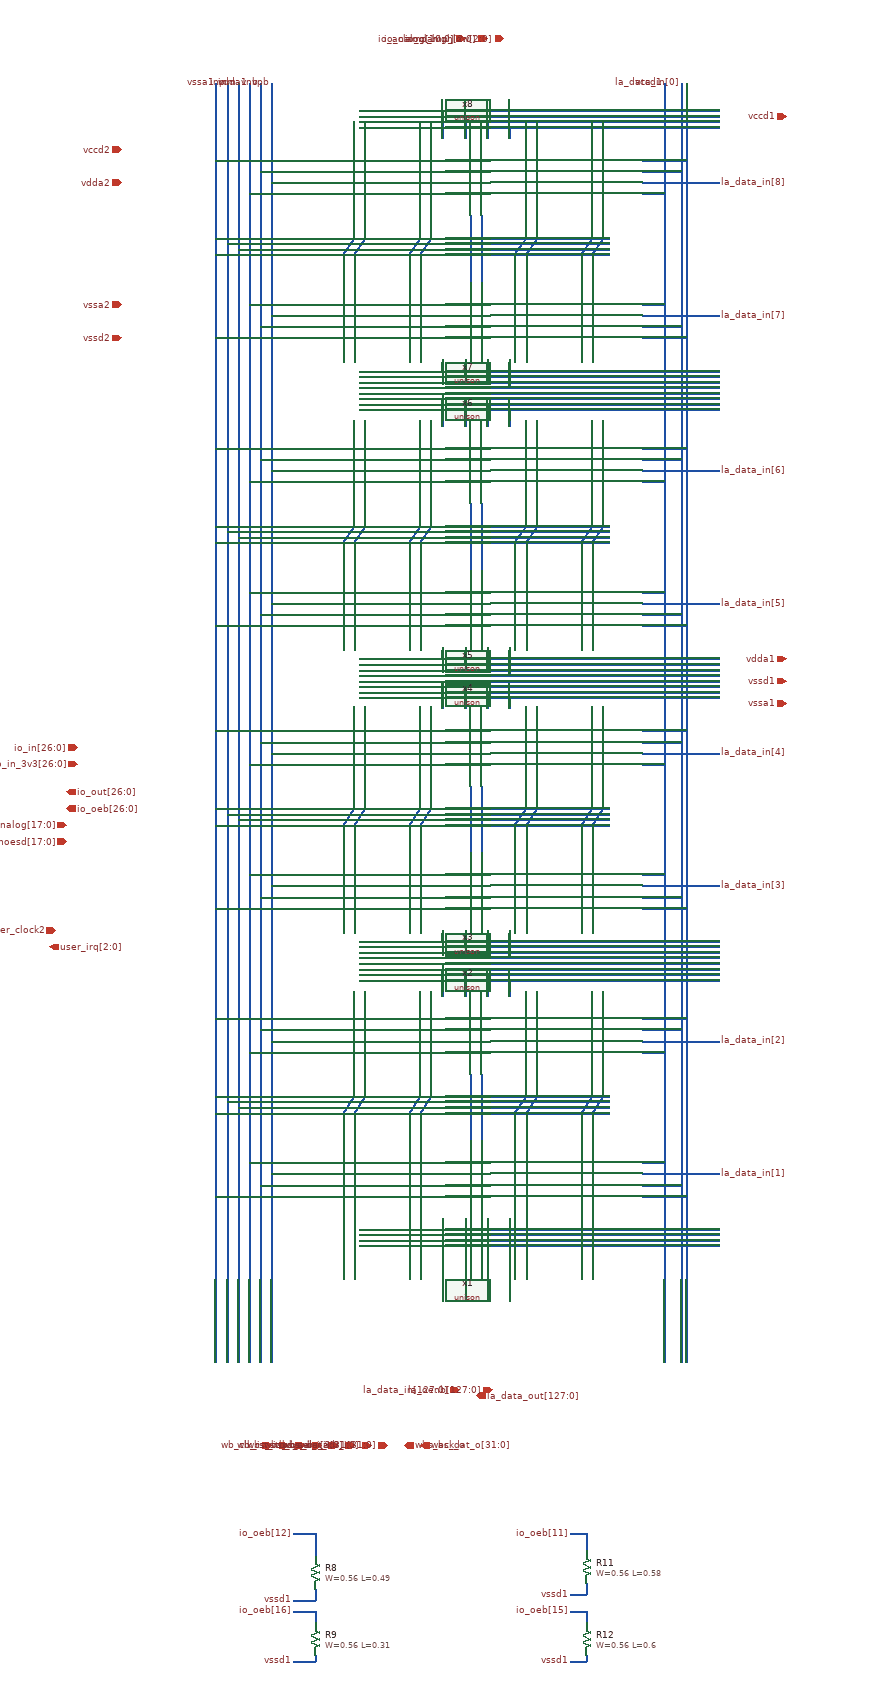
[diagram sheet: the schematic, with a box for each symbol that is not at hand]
v {xschem version=3.0.0 file_version=1.2 }
G {}
K {}
V {}
S {}
E {}
N -290 1540 -290 1580 { lab=io_oeb[12]}
N -290 1640 -290 1660 { lab=vssd1}
N -290 1680 -290 1700 { lab=io_oeb[16]}
N -290 1760 -290 1770 { lab=vssd1}
N 200 1540 200 1570 { lab=io_oeb[11]}
N 200 1630 200 1650 { lab=vssd1}
N 200 1680 200 1700 { lab=io_oeb[15]}
N 200 1760 200 1770 { lab=vssd1}
N -330 1540 -290 1540 { lab=io_oeb[12]}
N -330 1660 -290 1660 { lab=vssd1}
N -330 1680 -290 1680 { lab=io_oeb[16]}
N -330 1770 -290 1770 { lab=vssd1}
N 170 1540 200 1540 { lab=io_oeb[11]}
N 170 1650 200 1650 { lab=vssd1}
N 170 1680 200 1680 { lab=io_oeb[15]}
N 170 1770 200 1770 { lab=vssd1}
N -450 240 240 240 {
lab=inp}
N -430 250 240 250 {
lab=inm}
N -470 230 240 230 {
lab=vssa1}
N -470 260 240 260 {
lab=vssa1}
N -10 190 -10 240 {
lab=inp}
N -10 240 -10 310 {
lab=inp}
N 10 190 10 250 {
lab=inm}
N 10 250 10 310 {
lab=inm}
N -100 260 -80 230 {
lab=vssa1}
N -120 260 -100 230 {
lab=vssa1}
N 210 260 230 230 {
lab=vssa1}
N 190 260 210 230 {
lab=vssa1}
N -210 470 440 470 {
lab=#net1}
N -210 480 440 480 {
lab=#net2}
N -210 490 440 490 {
lab=#net3}
N -210 500 440 500 {
lab=#net4}
N -20 450 -20 480 {
lab=#net2}
N 20 450 20 490 {
lab=#net3}
N 60 450 60 500 {
lab=#net4}
N -60 450 -60 470 {
lab=#net1}
N -450 -1080 -450 1230 {
lab=inp}
N -390 -1080 -390 1230 {
lab=vnb}
N -410 -1080 -410 1230 {
lab=vdda1}
N -430 -1080 -430 1230 {
lab=inm}
N -470 -1080 -470 1230 {
lab=vssa1}
N -470 90 -280 90 {
lab=vssa1}
N -410 150 -280 150 {
lab=vdda1}
N -370 -1080 -370 1230 {
lab=vpb}
N -390 110 -280 110 {
lab=vnb}
N -370 130 -280 130 {
lab=vpb}
N -210 510 440 510 {
lab=#net5}
N -210 520 440 520 {
lab=#net6}
N -210 530 440 530 {
lab=#net7}
N -210 540 440 540 {
lab=#net8}
N -60 510 -60 570 {
lab=#net5}
N -20 520 -20 570 {
lab=#net6}
N 20 530 20 570 {
lab=#net7}
N 60 540 60 570 {
lab=#net8}
N 300 150 340 150 {
lab=vccd1}
N 300 350 340 350 {
lab=vccd1}
N 300 110 370 110 {
lab=la_data_in[0]}
N 370 -1080 370 1230 {
lab=la_data_in[0]}
N 300 90 380 90 {
lab=#net9}
N 380 -1080 380 1230 {
lab=#net9}
N 300 390 370 390 {
lab=la_data_in[0]}
N 300 410 380 410 {
lab=#net9}
N -220 260 -200 230 {
lab=vssa1}
N -240 260 -220 230 {
lab=vssa1}
N 90 260 110 230 {
lab=vssa1}
N 70 260 90 230 {
lab=vssa1}
N -410 350 -280 350 {
lab=vdda1}
N -370 370 -280 370 {
lab=vpb}
N -390 390 -280 390 {
lab=vnb}
N -470 410 -280 410 {
lab=vssa1}
N -210 0 440 0 {
lab=#net10}
N -210 10 440 10 {
lab=#net11}
N -210 20 440 20 {
lab=#net12}
N -210 30 440 30 {
lab=#net13}
N -60 0 -60 50 {
lab=#net10}
N -20 10 -20 50 {
lab=#net11}
N 20 20 20 50 {
lab=#net12}
N 60 30 60 50 {
lab=#net13}
N -450 760 240 760 {
lab=inp}
N -430 770 240 770 {
lab=inm}
N -470 750 240 750 {
lab=vssa1}
N -470 780 240 780 {
lab=vssa1}
N -10 710 -10 760 {
lab=inp}
N -10 760 -10 830 {
lab=inp}
N 10 710 10 770 {
lab=inm}
N 10 770 10 830 {
lab=inm}
N -100 780 -80 750 {
lab=vssa1}
N -120 780 -100 750 {
lab=vssa1}
N 210 780 230 750 {
lab=vssa1}
N 190 780 210 750 {
lab=vssa1}
N -220 780 -200 750 {
lab=vssa1}
N -240 780 -220 750 {
lab=vssa1}
N 90 780 110 750 {
lab=vssa1}
N 70 780 90 750 {
lab=vssa1}
N -210 990 440 990 {
lab=#net14}
N -210 1000 440 1000 {
lab=#net15}
N -210 1010 440 1010 {
lab=#net16}
N -210 1020 440 1020 {
lab=#net17}
N -20 970 -20 1000 {
lab=#net15}
N 20 970 20 1010 {
lab=#net16}
N 60 970 60 1020 {
lab=#net17}
N -60 970 -60 990 {
lab=#net14}
N -470 610 -280 610 {
lab=vssa1}
N -410 670 -280 670 {
lab=vdda1}
N -390 630 -280 630 {
lab=vnb}
N -370 650 -280 650 {
lab=vpb}
N -410 870 -280 870 {
lab=vdda1}
N -370 890 -280 890 {
lab=vpb}
N -390 910 -280 910 {
lab=vnb}
N -470 930 -280 930 {
lab=vssa1}
N 340 -1080 340 1230 {
lab=vccd1}
N 300 670 340 670 {
lab=vccd1}
N 300 630 370 630 {
lab=la_data_in[0]}
N 300 610 380 610 {
lab=#net9}
N -450 -790 240 -790 {
lab=inp}
N -430 -780 240 -780 {
lab=inm}
N -470 -800 240 -800 {
lab=vssa1}
N -470 -770 240 -770 {
lab=vssa1}
N -10 -840 -10 -790 {
lab=inp}
N -10 -790 -10 -720 {
lab=inp}
N 10 -840 10 -780 {
lab=inm}
N 10 -780 10 -720 {
lab=inm}
N -100 -770 -80 -800 {
lab=vssa1}
N -120 -770 -100 -800 {
lab=vssa1}
N 210 -770 230 -800 {
lab=vssa1}
N 190 -770 210 -800 {
lab=vssa1}
N -210 -560 440 -560 {
lab=#net18}
N -210 -550 440 -550 {
lab=#net19}
N -210 -540 440 -540 {
lab=#net20}
N -210 -530 440 -530 {
lab=#net21}
N -20 -580 -20 -550 {
lab=#net19}
N 20 -580 20 -540 {
lab=#net20}
N 60 -580 60 -530 {
lab=#net21}
N -60 -580 -60 -560 {
lab=#net18}
N -470 -940 -280 -940 {
lab=vssa1}
N -410 -880 -280 -880 {
lab=vdda1}
N -390 -920 -280 -920 {
lab=vnb}
N -370 -900 -280 -900 {
lab=vpb}
N -210 -520 440 -520 {
lab=#net22}
N -210 -510 440 -510 {
lab=#net23}
N -210 -500 440 -500 {
lab=#net24}
N -210 -490 440 -490 {
lab=#net25}
N -60 -520 -60 -460 {
lab=#net22}
N -20 -510 -20 -460 {
lab=#net23}
N 20 -500 20 -460 {
lab=#net24}
N 60 -490 60 -460 {
lab=#net25}
N 300 -880 340 -880 {
lab=vccd1}
N 300 -680 340 -680 {
lab=vccd1}
N 300 -900 440 -900 {
lab=la_data_in[8]}
N 300 -920 370 -920 {
lab=la_data_in[0]}
N 300 -940 380 -940 {
lab=#net9}
N 300 -640 370 -640 {
lab=la_data_in[0]}
N 300 -620 380 -620 {
lab=#net9}
N -220 -770 -200 -800 {
lab=vssa1}
N -240 -770 -220 -800 {
lab=vssa1}
N 90 -770 110 -800 {
lab=vssa1}
N 70 -770 90 -800 {
lab=vssa1}
N -410 -680 -280 -680 {
lab=vdda1}
N -370 -660 -280 -660 {
lab=vpb}
N -390 -640 -280 -640 {
lab=vnb}
N -470 -620 -280 -620 {
lab=vssa1}
N -210 -1030 440 -1030 {
lab=#net26}
N -210 -1020 440 -1020 {
lab=#net27}
N -210 -1010 440 -1010 {
lab=#net28}
N -210 -1000 440 -1000 {
lab=#net29}
N -60 -1030 -60 -980 {
lab=#net26}
N -20 -1020 -20 -980 {
lab=#net27}
N 20 -1010 20 -980 {
lab=#net28}
N 60 -1000 60 -980 {
lab=#net29}
N -450 -270 240 -270 {
lab=inp}
N -430 -260 240 -260 {
lab=inm}
N -470 -280 240 -280 {
lab=vssa1}
N -470 -250 240 -250 {
lab=vssa1}
N -10 -320 -10 -270 {
lab=inp}
N -10 -270 -10 -200 {
lab=inp}
N 10 -320 10 -260 {
lab=inm}
N 10 -260 10 -200 {
lab=inm}
N -100 -250 -80 -280 {
lab=vssa1}
N -120 -250 -100 -280 {
lab=vssa1}
N 210 -250 230 -280 {
lab=vssa1}
N 190 -250 210 -280 {
lab=vssa1}
N -220 -250 -200 -280 {
lab=vssa1}
N -240 -250 -220 -280 {
lab=vssa1}
N 90 -250 110 -280 {
lab=vssa1}
N 70 -250 90 -280 {
lab=vssa1}
N -210 -40 440 -40 {
lab=#net30}
N -210 -30 440 -30 {
lab=#net31}
N -210 -20 440 -20 {
lab=#net32}
N -210 -10 440 -10 {
lab=#net33}
N -20 -60 -20 -30 {
lab=#net31}
N 20 -60 20 -20 {
lab=#net32}
N 60 -60 60 -10 {
lab=#net33}
N -60 -60 -60 -40 {
lab=#net30}
N -470 -420 -280 -420 {
lab=vssa1}
N -410 -360 -280 -360 {
lab=vdda1}
N -390 -400 -280 -400 {
lab=vnb}
N -370 -380 -280 -380 {
lab=vpb}
N -410 -160 -280 -160 {
lab=vdda1}
N -370 -140 -280 -140 {
lab=vpb}
N -390 -120 -280 -120 {
lab=vnb}
N -470 -100 -280 -100 {
lab=vssa1}
N 300 -360 340 -360 {
lab=vccd1}
N 300 -400 370 -400 {
lab=la_data_in[0]}
N 300 -420 380 -420 {
lab=#net9}
N 300 -660 440 -660 {
lab=la_data_in[7]}
N 300 -380 440 -380 {
lab=la_data_in[6]}
N 300 -140 440 -140 {
lab=la_data_in[5]}
N 300 -120 370 -120 {
lab=la_data_in[0]}
N 300 910 370 910 {
lab=la_data_in[0]}
N 300 130 440 130 {
lab=la_data_in[4]}
N 300 370 440 370 {
lab=la_data_in[3]}
N 300 650 440 650 {
lab=la_data_in[2]}
N 300 890 440 890 {
lab=la_data_in[1]}
N 300 870 340 870 {
lab=vccd1}
N 300 930 380 930 {
lab=#net9}
N 300 -160 340 -160 {
lab=vccd1}
N 300 -100 380 -100 {
lab=#net9}
C {devices/iopin.sym} 560 -40 0 0 {name=p1 lab=vdda1}
C {devices/iopin.sym} -640 -900 2 0 {name=p2 lab=vdda2}
C {devices/iopin.sym} 560 40 0 0 {name=p3 lab=vssa1}
C {devices/iopin.sym} -640 -680 2 0 {name=p4 lab=vssa2}
C {devices/iopin.sym} 560 -1020 0 0 {name=p5 lab=vccd1}
C {devices/iopin.sym} -640 -960 2 0 {name=p6 lab=vccd2}
C {devices/iopin.sym} 560 0 0 0 {name=p7 lab=vssd1}
C {devices/iopin.sym} -640 -620 2 0 {name=p8 lab=vssd2}
C {devices/ipin.sym} -370 1380 3 0 {name=p9 lab=wb_clk_i}
C {devices/ipin.sym} -340 1380 3 0 {name=p10 lab=wb_rst_i}
C {devices/ipin.sym} -310 1380 3 0 {name=p11 lab=wbs_stb_i}
C {devices/ipin.sym} -280 1380 3 0 {name=p12 lab=wbs_cyc_i}
C {devices/ipin.sym} -250 1380 3 0 {name=p13 lab=wbs_we_i}
C {devices/ipin.sym} -220 1380 3 0 {name=p14 lab=wbs_sel_i[3:0]}
C {devices/ipin.sym} -190 1380 3 0 {name=p15 lab=wbs_dat_i[31:0]}
C {devices/ipin.sym} -160 1380 3 0 {name=p16 lab=wbs_adr_i[31:0]}
C {devices/opin.sym} -130 1380 3 0 {name=p17 lab=wbs_ack_o}
C {devices/opin.sym} -100 1380 3 0 {name=p18 lab=wbs_dat_o[31:0]}
C {devices/ipin.sym} -30 1280 3 0 {name=p19 lab=la_data_in[127:0]}
C {devices/opin.sym} 0 1290 3 0 {name=p20 lab=la_data_out[127:0]}
C {devices/ipin.sym} -720 120 0 0 {name=p21 lab=io_in[26:0]}
C {devices/ipin.sym} -720 150 0 0 {name=p22 lab=io_in_3v3[26:0]}
C {devices/ipin.sym} -760 450 0 0 {name=p23 lab=user_clock2}
C {devices/opin.sym} -740 200 0 0 {name=p24 lab=io_out[26:0]}
C {devices/opin.sym} -740 230 0 0 {name=p25 lab=io_oeb[26:0]}
C {devices/iopin.sym} -740 260 0 0 {name=p26 lab=gpio_analog[17:0]}
C {devices/iopin.sym} -740 290 0 0 {name=p27 lab=gpio_noesd[17:0]}
C {devices/iopin.sym} -20 -1160 3 0 {name=p29 lab=io_analog[10:0]}
C {devices/iopin.sym} 20 -1160 3 0 {name=p30 lab=io_clamp_high[2:0]}
C {devices/iopin.sym} 50 -1160 3 0 {name=p31 lab=io_clamp_low[2:0]}
C {devices/opin.sym} -770 480 0 0 {name=p32 lab=user_irq[2:0]}
C {devices/ipin.sym} 30 1280 3 0 {name=p28 lab=la_oenb[127:0]}
C {sky130_fd_pr/res_generic_m1.sym} -290 1610 0 0 {name=R8
W=0.56
L=0.49
model=res_generic_m3
mult=1}
C {sky130_fd_pr/res_generic_m1.sym} -290 1730 0 0 {name=R9
W=0.56
L=0.31
model=res_generic_m3
mult=1}
C {sky130_fd_pr/res_generic_m1.sym} 200 1600 0 0 {name=R11
W=0.56
L=0.58
model=res_generic_m3
mult=1}
C {sky130_fd_pr/res_generic_m1.sym} 200 1730 0 0 {name=R12
W=0.56
L=0.6
model=res_generic_m3
mult=1}
C {devices/lab_pin.sym} 170 1680 0 0 {name=l25 sig_type=std_logic lab=io_oeb[15]}
C {devices/lab_pin.sym} -330 1680 0 0 {name=l26 sig_type=std_logic lab=io_oeb[16]}
C {devices/lab_pin.sym} 170 1540 0 0 {name=l27 sig_type=std_logic lab=io_oeb[11]}
C {devices/lab_pin.sym} -330 1540 0 0 {name=l28 sig_type=std_logic lab=io_oeb[12]}
C {devices/lab_pin.sym} -330 1660 0 0 {name=l29 sig_type=std_logic lab=vssd1}
C {devices/lab_pin.sym} -330 1770 0 0 {name=l30 sig_type=std_logic lab=vssd1}
C {devices/lab_pin.sym} 170 1650 0 0 {name=l31 sig_type=std_logic lab=vssd1}
C {devices/lab_pin.sym} 170 1770 0 0 {name=l32 sig_type=std_logic lab=vssd1}
C {top/unison.sym} 0 890 0 0 {name=x1}
C {top/unison.sym} 0 650 2 1 {name=x2}
C {top/unison.sym} 0 370 0 0 {name=x3}
C {top/unison.sym} 0 130 2 1 {name=x4}
C {top/unison.sym} 0 -140 0 0 {name=x5}
C {top/unison.sym} 0 -380 2 1 {name=x6}
C {top/unison.sym} 0 -660 0 0 {name=x7}
C {top/unison.sym} 0 -900 2 1 {name=x8}
C {devices/lab_pin.sym} -470 -1080 1 0 {name=l1 sig_type=std_logic lab=vssa1}
C {devices/lab_pin.sym} -390 -1080 1 0 {name=l2 sig_type=std_logic lab=vnb}
C {devices/lab_pin.sym} -370 -1080 1 0 {name=l3 sig_type=std_logic lab=vpb}
C {devices/lab_pin.sym} -410 -1080 1 0 {name=l4 sig_type=std_logic lab=vdda1}
C {devices/lab_pin.sym} -450 -1080 1 0 {name=l5 sig_type=std_logic lab=inp}
C {devices/lab_pin.sym} -430 -1080 1 0 {name=l6 sig_type=std_logic lab=inm}
C {devices/lab_pin.sym} 340 -1080 1 0 {name=l7 sig_type=std_logic lab=vccd1}
C {devices/lab_pin.sym} 440 -900 2 0 {name=l8 sig_type=std_logic lab=la_data_in[8]}
C {devices/lab_pin.sym} 440 -660 2 0 {name=l9 sig_type=std_logic lab=la_data_in[7]}
C {devices/lab_pin.sym} 370 -1080 1 0 {name=l10 sig_type=std_logic lab=la_data_in[0]}
C {devices/lab_pin.sym} 440 -380 2 0 {name=l11 sig_type=std_logic lab=la_data_in[6]}
C {devices/lab_pin.sym} 440 -140 2 0 {name=l12 sig_type=std_logic lab=la_data_in[5]}
C {devices/lab_pin.sym} 440 130 2 0 {name=l13 sig_type=std_logic lab=la_data_in[4]}
C {devices/lab_pin.sym} 440 370 2 0 {name=l14 sig_type=std_logic lab=la_data_in[3]}
C {devices/lab_pin.sym} 440 650 2 0 {name=l15 sig_type=std_logic lab=la_data_in[2]}
C {devices/lab_pin.sym} 440 890 2 0 {name=l16 sig_type=std_logic lab=la_data_in[1]}
